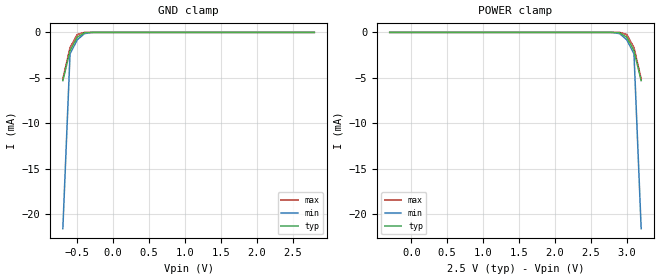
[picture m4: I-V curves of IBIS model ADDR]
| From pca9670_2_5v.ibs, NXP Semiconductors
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[Model]   ADDR
Model_type Input
Vinh=1.5
Vinl=0.75
C_comp   1.7p   1.5p   1.9p
[Model Spec]
Vinh   2.31   1.61   3.85
Vinl   0.99   0.69   1.65
[Temperature Range] 27   85   -40
[Voltage Range]   2.5   2.2   2.8
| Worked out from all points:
|   GND clamp passes 1 mA (typ) near -0.53 V on its own axis
[GND Clamp]
-700mV    -5.302mA   -21.58mA   -5.122mA
-600mV    -2.04mA    -2.358mA   -1.687mA
-500mV    -525.2uA   -816.9uA   -228.9uA
-400mV    -48.21uA   -135uA     -7.763uA
-200mV    -27.28nA   -200nA     -811.9pA
2.8V      51pA       210.6pA    36.58pA
[POWER Clamp]
-300mV    51pA       210.6pA    36.58pA
2.7V      -27.28nA   -200nA     -811.9pA
2.9V      -48.21uA   -135uA     -7.763uA
3V        -525.2uA   -816.9uA   -228.9uA
3.1V      -2.04mA    -2.358mA   -1.687mA
3.2V      -5.302mA   -21.58mA   -5.122mA
